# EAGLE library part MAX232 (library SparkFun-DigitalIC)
RS232 Transceiver Very common IC. This is generically called 'MAX232', but works with the 3V equivalent MAX3232 generic ICs. Field tested and mother approved. Spark Fun Electronics SKU : COM-00316 (DIP) and COM-00589 (SMD)

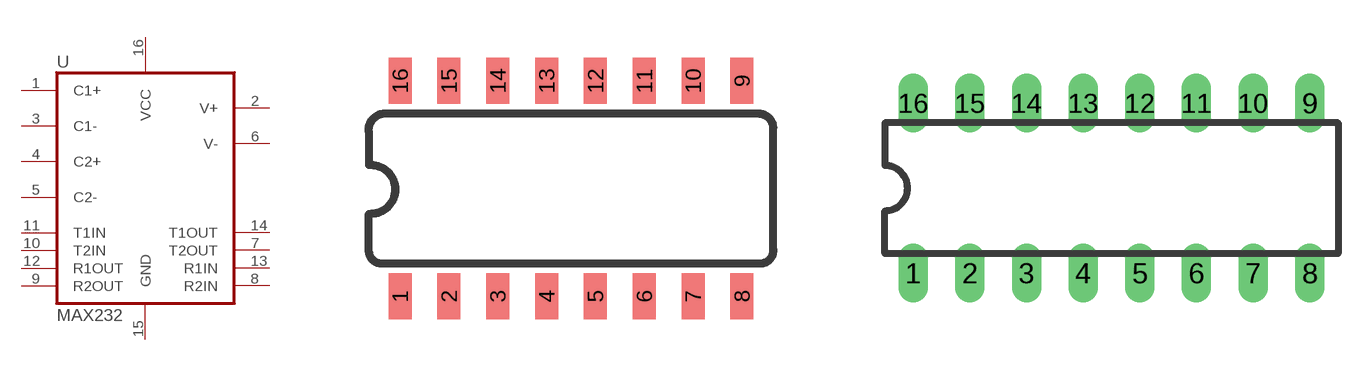
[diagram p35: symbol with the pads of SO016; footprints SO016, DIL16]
Designator prefix U

## MAX232SOIC16 (PROD_ID: IC-08171)  [SO016]
1  C1+
2  V+
3  C1-
4  C2+
5  C2-
6  V-
7  T2OUT  out
8  R2IN  in
9  R2OUT  out
10  T2IN  in
11  T1IN  in
12  R1OUT  out
13  R1IN  in
14  T1OUT  out
15  GND
16  VCC

## MAX232PTH  [DIL16]
Pads as for SO016

## MAX232TSSOP  [TSSOP16]
Pads as for SO016

## Footprint SO016 (pad centres in mm)
smd 0.6 x 1.2: 1 -4.445,-2.8; 2 -3.175,-2.8; 3 -1.905,-2.8; 4 -0.635,-2.8; 5 0.635,-2.8; 6 1.905,-2.8; 7 3.175,-2.8; 8 4.445,-2.8; 9 4.445,2.8; 10 3.175,2.8; 11 1.905,2.8; 12 0.635,2.8; 13 -0.635,2.8; 14 -1.905,2.8; 15 -3.175,2.8; 16 -4.445,2.8

## Footprint DIL16 (pad centres in mm)
Dual In Line Package
drill 0.813 long: 1 -8.89,-3.81; 2 -6.35,-3.81; 3 -3.81,-3.81; 4 -1.27,-3.81; 5 1.27,-3.81; 6 3.81,-3.81; 7 6.35,-3.81; 8 8.89,-3.81; 9 8.89,3.81; 10 6.35,3.81; 11 3.81,3.81; 12 1.27,3.81; 13 -1.27,3.81; 14 -3.81,3.81; 15 -6.35,3.81; 16 -8.89,3.81

## Footprint TSSOP16 (pad centres in mm)
TSOP16 thin small outline package
smd 0.4 x 1.6: 1 -2.225,-2.85; 2 -1.575,-2.85; 3 -0.925,-2.85; 4 -0.275,-2.85; 5 0.375,-2.85; 6 1.025,-2.85; 7 1.675,-2.85; 8 2.325,-2.85; 9 2.325,3.05; 10 1.675,3.05; 11 1.025,3.05; 12 0.375,3.05; 13 -0.275,3.05; 14 -0.925,3.05; 15 -1.575,3.05; 16 -2.225,3.05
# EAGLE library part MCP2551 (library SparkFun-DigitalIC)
CAN transceiver

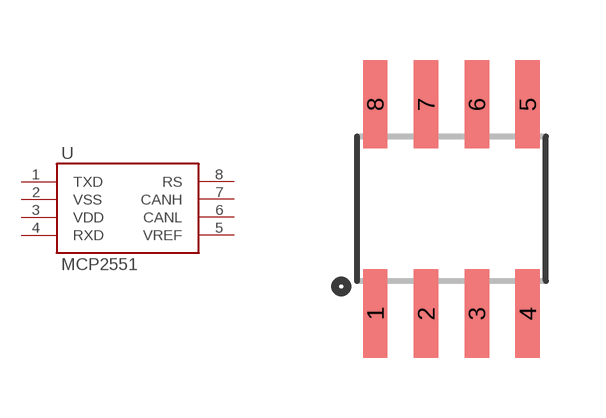
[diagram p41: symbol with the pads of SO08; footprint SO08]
Designator prefix U

## MCP2551 (PROD_ID: IC-09907)  [SO08]
1  TXD
2  VSS
3  VDD
4  RXD
5  VREF
6  CANL
7  CANH
8  RS

## Footprint SO08 (pad centres in mm)
Small Outline Package Fits JEDEC packages (narrow SOIC-8)
smd 0.61 x 2.21: 1 -1.905,-2.616; 2 -0.635,-2.616; 3 0.635,-2.616; 4 1.905,-2.616; 5 1.905,2.616; 6 0.635,2.616; 7 -0.635,2.616; 8 -1.905,2.616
